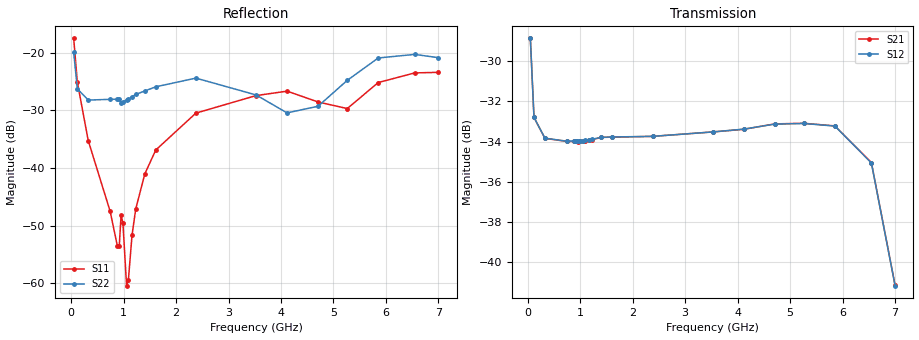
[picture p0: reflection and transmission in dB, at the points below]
! Integrated Device Technology
! Corporate Headquarters
! 6024 Silver Creek Valley Road
! San Jose, CA 95138  USA
! Phone:  1-408-284-8200
! Toll Free:  1-800-223-1366
! Webpage:  http://www.idt.com/
! Timing and RF Division
! 515 Groton Road, Suite 102
! Westford, MA 01886-6024
! Device:  F2258
! Description: Voltage Variable RF Attenuator
! Frequency:  50.0 -  6000.00 MHz
! Package:  3x3 mm Thin QFN Plastic Package: 16 pin
! Ports:  2 RF, 2 DC
!  Pin  1  = NC
!  Pin  2  = NC
!  Pin  3  = RF2  = Port 2
!  Pin  4  = GND
!  Pin  5  = Vdd
!  Pin  6  = NC
!  Pin  7  = VCTRL
!  Pin  8  = NC
!  Pin  9  = GND
!  Pin 10  = RF1  = Port 1
!  Pin 11  = NC
!  Pin 12  = NC
!  Pin 13  = NC
!  Pin 14  = NC
!  Pin 15  = NC
!  Pin 16  = NC
! Vcntrl:  1.840 Volts
! Vdd:  +3.300 Volts
! Current:  1.158 mA
! Data:  The device was measured on a the F2258 evaluation board which has
!  individual transmission lines to the RF pins.  Data was collected
!  using a calibrated network analyzer.  The evaluation board was
!  de-embedded using a TRL calibration technique.
!  The reference plane is the edge of the package pin.
! Misc:  SN 10
!  Action Tracker AT0285
! Date Measured:  2014-12-10
! Date:  2016-01-13  MJV
! Note:
!  Integrated Device Technology supplies this data as a sample of measured
!  data at the package pin for this product.  Your particular data for this
!  product may vary.
!  Data was taken at 25 degrees C.
!  Integrated Device Technology reserves the right to change this data at anytime.
!Freq_(GHz)  S11M_(dB)  S11P_(deg)  S21M_(dB)  S21P_(deg)  S12M_(dB)  S12P_(deg)  S22M_(dB)  S22P_(deg)
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# GHz S dB R 50
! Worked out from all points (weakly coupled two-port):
!   201 points, 50 MHz to 7 GHz, reference 50 ohm
!   highest |S21| = -28.87 dB at 50 MHz (marker M1); lowest = -41.1 dB at 7 GHz (marker M2)
!   lowest |S11| = -60.4 dB at 1.058 GHz (marker M3), VSWR 1.00, Z = 49.9 + j0.0454 ohm
!   |S11| at or under -10 dB: start of sweep to end of sweep
!   |S22| runs from -31.0 to -19.9 dB; largest |S21 - S12| = 7.8e-05
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0.05  -17.54 -110.7  -28.87 -62.5  -28.87 -62.5  -19.97 -97.6
0.1195  -25.12 -106.4  -32.80 -33.1  -32.80 -33.1  -26.28 -57.1
0.328  -35.29 -113.8  -33.84 -14.3  -33.83 -14.3  -28.24 -19.7
0.745  -47.53 -139.4  -33.99 -9.5  -33.98 -9.5  -28.11 -4.8
0.884  -53.61 167.4  -33.99 -9.2  -33.97 -9.2  -28.09 -4.4
0.91875  -53.47 147.7  -33.99 -9.2  -33.97 -9.2  -28.08 -4.3
0.9535  -48.22 -159.1  -34.01 -9.1  -33.99 -9.1  -28.76 -1.1
0.98825  -49.54 -171.2  -33.99 -9.1  -33.97 -9.1  -28.65 -2.0
1.05775  -60.42 151.5  -33.98 -9.1  -33.95 -9.1  -28.18 -1.6
1.0925  -59.44 106.6  -33.96 -9.1  -33.94 -9.1  -28.06 -1.6
1.162  -51.63 62.3  -33.93 -9.2  -33.91 -9.2  -27.64 -1.6
1.2315  -47.16 42.1  -33.90 -9.4  -33.88 -9.4  -27.26 -1.7
1.40525  -41.04 31.6  -33.79 -10.3  -33.79 -10.3  -26.66 -0.8
1.61375  -36.90 31.4  -33.78 -11.5  -33.77 -11.5  -25.94 -2.0
2.37825  -30.50 47.4  -33.74 -15.9  -33.74 -15.9  -24.43 -0.6
3.525  -27.46 91.3  -33.52 -23.4  -33.52 -23.4  -27.35 10.5
4.11575  -26.69 104.8  -33.39 -27.7  -33.38 -27.7  -30.46 11.5
4.7065  -28.57 95.4  -33.12 -33.1  -33.13 -33.1  -29.31 -6.1
5.2625  -29.71 53.8  -33.09 -39.3  -33.10 -39.2  -24.82 -22.6
5.85325  -25.20 29.5  -33.22 -49.3  -33.23 -49.2  -20.94 -28.9
6.54825  -23.53 44.8  -35.04 -67.9  -35.06 -67.9  -20.32 -57.7
7  -23.43 84.3  -41.14 -64.8  -41.16 -64.5  -20.89 -124.3
